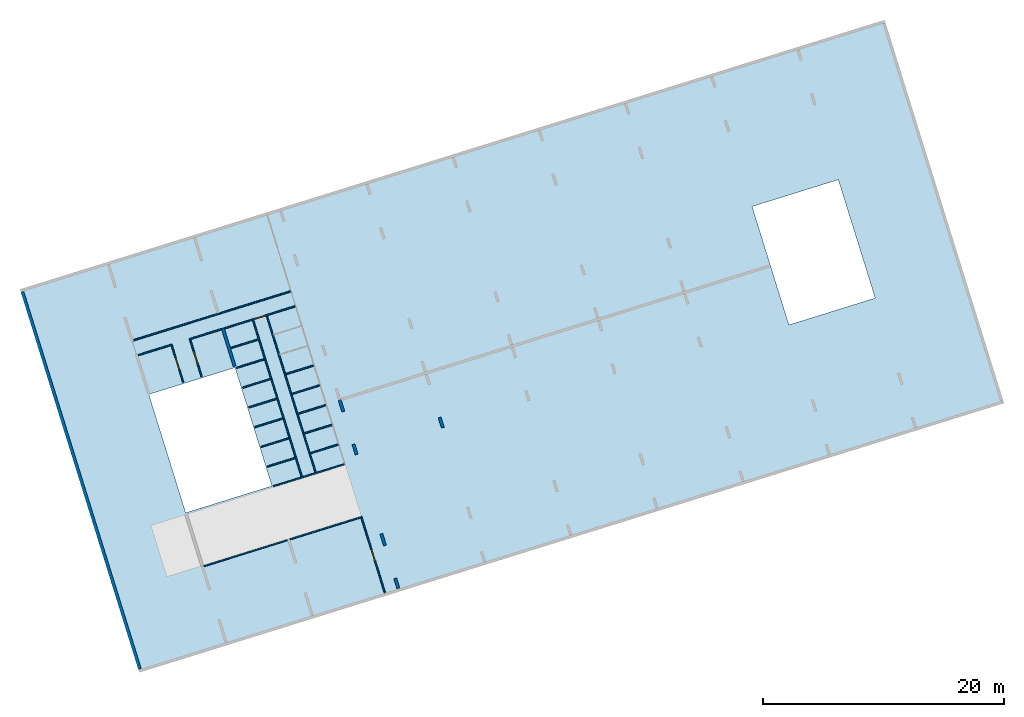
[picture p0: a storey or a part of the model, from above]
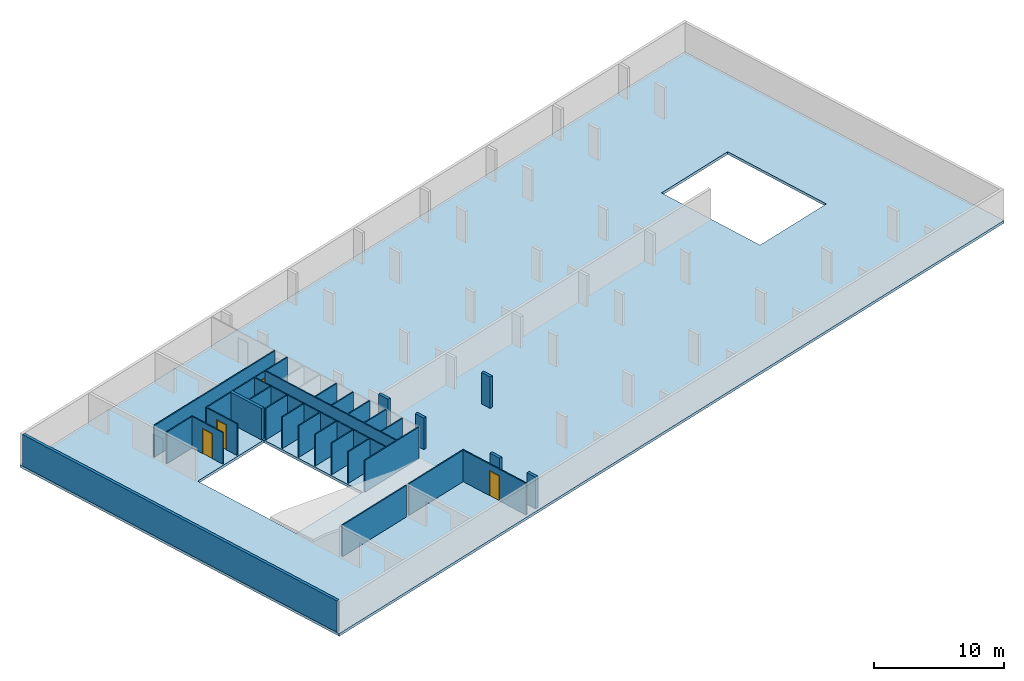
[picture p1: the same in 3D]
Properties of the parts of a building model (IFC4)

# File
Description: ViewDefinition [ReferenceView_V1.2], RevitIdentifiers [ContentGUID: 7b0fba1c-e461-43e6-a004-74300536da52, VersionGUID: d83a99a4-e321-4da3-b3c9-0b0068a0408a, NumberOfSaves: 137], Options [Excluded Entities: IfcGroup;], CoordinateReference [CoordinateBase: Survey Point, ProjectSite: Internal]
File name: MiniBIM 3.1 SO_00_VORM.ifc
Time: 2025-10-09T12:54:53+02:00
Organization: VORM Holding B.V.
Written by: IfcOpenShell 0.8.2
Made in: Bonsai 0.8.2

# IfcProject, 0000
LongName: Voorbeelmodel MiniBIM 3.1 SO-fase; Phase: PROJECTFASE

# IfcSite, Schiehaven
RefLatitude: 51, 54, 13, 78253; RefLongitude: 4, 27, 15, 99642; RefElevation: 3.5 m
Pset_SiteCommon - Reference: Project Information

# IfcBuilding, VORM huis
LongName: VORM huis
Pset_BuildingCommon - Reference: Project Information; NumberOfStoreys: 2; IsLandmarked: no
Pset_BuildingElementProxyCommon - Reference: Project Information; IsExternal: no
Pset_BuildingStoreyCommon - Reference: Project Information; AboveGround: no
Pset_BuildingSystemCommon - Reference: Project Information

# IfcBuildingStorey: Level:Level bouwniveau (PBP) (11)
In: VORM huis
Pset_BuildingStoreyCommon - Reference: Level bouwniveau (PBP)
Name | LongName | Elevation (m) | EntranceLevel | AboveGround
-1 kelder | -1 kelder | -3.2 | no | no
00 begane grond | begane grond | 0 | yes | yes
01 eerste verdieping | 01 eerste verdieping | 3.9 | no | yes
02 tweede verdieping | 02 tweede verdieping | 6.9 | no | yes
03 derde verdieping | 03 derde verdieping | 9.9 | no | yes
04 vierde verdieping | 04 vierde verdieping | 12.9 | no | yes
05 vijfde verdieping | 05 vijfde verdieping | 15.9 | no | yes
06 zesde verdieping | 06 zesde verdieping | 18.9 | no | yes
07 zevende verdieping | 07 zevende verdieping | 21.9 | no | yes
08 achtste verdieping | 08 achtste verdieping | 24.9 | no | yes
09 negende verdieping | 09 negende verdieping | 27.9 | no | yes

# IfcBuildingElementProxy: VORM_coordinatiepunt:CRS-coordinatiepunt, CRS-coordinatiepunt
In: 00 begane grond
Type - Classification: 00.00 (NL-SfB); Material: Blauw, Wit
Pset_BuildingElementProxyCommon - IsExternal: no; Reference: CRS-coordinatiepunt
Pset_EnvironmentalImpactIndicators - Reference: CRS-coordinatiepunt
Qto_BuildingElementProxyQuantities - NetSurfaceArea: 6.92096 m2; NetVolume: 0.458368 m3

# IfcBuildingElementProxy: VORM_coordinatiepunt:Lokaal-coordinatiepunt, Lokaal-coordinatiepunt
In: 00 begane grond
Type - Classification: 00.00 (NL-SfB); Material: Blauw, Wit
Pset_BuildingElementProxyCommon - Reference: Lokaal-coordinatiepunt; IsExternal: no
Pset_EnvironmentalImpactIndicators - Reference: Lokaal-coordinatiepunt
Qto_BuildingElementProxyQuantities - NetSurfaceArea: 7.78088 m2; NetVolume: 1.00022 m3

# IfcDoor: 32_DO_binnendeur enkel:binnendeur zelfsluitend 30min (7)
In: -1 kelder
Type - PredefinedType: DOOR; Classification: 32.30 binnenwandopeningen; gevuld met deuren, algemeen (verzamelniveau) (NL-SfB); Material: PD_a_binnenwandopeningen, metaal_aluminium_ntb
Type - Pset_DoorCommon - IsExternal: no; FireRating: 30
OverallHeight: 2.35 m; OverallWidth: 1.05 m
Pset_DoorCommon - Reference: binnendeur zelfsluitend 30min
Pset_EnvironmentalImpactIndicators - Reference: binnendeur zelfsluitend 30min
Qto_DoorBaseQuantities - Width: 1.05 m; Height: 2.35 m; Perimeter: 2 m; Area: 2.4675 m2
Name
3 x Vluchtdeur | MiniBIM ILS - BouwwerkNummer: 01
4 x Vluchtdeur

# IfcOpeningElement (14)
In: -1 kelder
PredefinedType: OPENING
Name | Depth (m) | Height (m) | Width (m)
4 x Constructieve wand | 0.25 | 2.4 | 2.55 | Pset_EnvironmentalImpactIndicators - Reference: 28_WA_skelet_wand 250mm_gen; sets with these values: 2
2 x Funderingvloer |  | 7.5 | 10.3 | Pset_EnvironmentalImpactIndicators - Reference: 13_FL_funderingvloer 250mm; sets with these values: 2
5 x Vluchtdeur | 0.1 | 1.05 | 2.35
Vluchtdeur | 0.1 | 2.35 | 1.05
Vluchtdeur | 0.25 | 1.05 | 2.35
Vluchtdeur | 3.048 | 2.35 | 1.05

# IfcRamp: 24_GM_TLB_hellingbaan:Stalling, Hellingbaan
In: -1 kelder
Classification: 24.20 trappen en hellingen; hellingen, algemeen (verzamelniveau) (NL-SfB); Material: beton_gewapend_ihw
Pset_EnvironmentalImpactIndicators - Reference: Stalling
Pset_RampCommon - IsExternal: no; Reference: Stalling
Pset_RampFlightCommon - Reference: Stalling; Slope: 12.1338 deg

# IfcSlab: Floor:13_FL_funderingvloer 250mm, Funderingvloer
In: -1 kelder
Type - PredefinedType: FLOOR; Material: beton_gewapend_ihw
Type - Pset_ReinforcementBarPitchOfSlab - Description: Funderingvloer
Type - Pset_SlabCommon - LoadBearing: yes
Classification: 13.20 vloeren op grondslag; constructief, algemeen (verzamelniveau) (NL-SfB)
Pset_EnvironmentalImpactIndicators - Reference: 13_FL_funderingvloer 250mm; sets with these values: 2
Pset_SlabCommon - IsExternal: no; LoadBearing: no; Reference: 13_FL_funderingvloer 250mm; PitchAngle: 0 deg
Qto_SlabBaseQuantities - Width: 33.35 m; Length: 75.25 m; Depth: 0.25 m; Perimeter: 946.194 m; GrossArea: 2509.59 m2; NetArea: 2355.09 m2; GrossVolume: 627.397 m3; NetVolume: 588.772 m3

# IfcSlab: Floor:28_FL_skelet_dakterrasvloer 250mm, Begaanbare dakvloer
In: 00 begane grond
Type - PredefinedType: ROOF; Material: beton_gewapend_ihw
Type - Pset_ReinforcementBarPitchOfSlab - Description: Begaanbare dakvloer
Type - Pset_SlabCommon - LoadBearing: yes
Classification: 27.10 daken; niet constructief, algemeen (verzamelniveau) (NL-SfB)
Pset_EnvironmentalImpactIndicators - Reference: 28_FL_skelet_dakterrasvloer 250mm; sets with these values: 2
Pset_SlabCommon - IsExternal: no; LoadBearing: no; PitchAngle: 0 deg; Reference: 28_FL_skelet_dakterrasvloer 250mm
Qto_SlabBaseQuantities - Width: 29.75 m; Length: 33.35 m; Depth: 0.25 m; Perimeter: 414.042 m; GrossArea: 992.163 m2; NetArea: 992.163 m2; GrossVolume: 248.041 m3; NetVolume: 248.041 m3

# IfcWall: Basic Wall:22_WA_afbouw_binnenwand 100mm_gen (27)
In: -1 kelder
Type - PredefinedType: STANDARD
Type - Pset_ReinforcementBarPitchOfWall - Description: Binnenwand
Type - Pset_WallCommon - LoadBearing: no
Classification: 22.10 binnenwanden; niet constructief, algemeen (verzamelniveau) (NL-SfB); Material: ntb_ntb_ntb
Qto_WallBaseQuantities - Height: 2.95 m; Width: 0.1 m
Pset_EnvironmentalImpactIndicators - Reference: 22_WA_afbouw_binnenwand 100mm_gen; sets with these values: 2
Pset_WallCommon - IsExternal: no; ExtendToStructure: no; Reference: 22_WA_afbouw_binnenwand 100mm_gen
Name | Length (m) | GrossFootprintArea (m2) | GrossVolume (m3) = NetVolume (m3) | GrossSideArea (m2) = NetSideArea (m2)
Binnenwand | 21.7 | 2.17 | 5.908 | 59.08
Binnenwand | 6.15 | 0.615 | 1.81425 | 18.1425
Binnenwand | 6.25 | 0.625 | 1.84375 | 18.4375
Binnenwand | 6.55 | 0.655 | 1.6855 | 16.855
Binnenwand | 7.25 | 0.725 | 2.13875 | 21.3875
3 x Binnenwand | 13.65 | 1.365 | 4.02675 | 40.2675
Binnenwand | 6.15 | 0.615 | 1.5675 | 15.675
Binnenwand | 3.2 | 0.32 | 0.69725 | 6.9725
Binnenwand | 3.3 | 0.33 | 0.72675 | 7.2675
Binnenwand | 2.85 | 0.285 | 0.84075 | 8.4075
Binnenwand | 2.8 | 0.28 | 0.826 | 8.26
14 x Binnenwand | 2.425 | 0.2425 | 0.715375 | 7.15375

# IfcWall: Basic Wall:28_WA_skelet_keerwand 250mm_gen (4)
In: -1 kelder
Type - PredefinedType: STANDARD
Type - Pset_ReinforcementBarPitchOfWall - Description: Constructieve keerwand
Type - Pset_WallCommon - LoadBearing: yes
Classification: 28.20 hoofddraagconstructies; wanden en vloeren, algemeen (verzamelniveau) (NL-SfB); Material: beton_gewapend_ihw
Qto_WallBaseQuantities - Height: 2.95 m; Width: 0.25 m
Pset_EnvironmentalImpactIndicators - Reference: 28_WA_skelet_keerwand 250mm_gen; sets with these values: 2
Pset_WallCommon - IsExternal: no; Reference: 28_WA_skelet_keerwand 250mm_gen; LoadBearing: no; ExtendToStructure: no
Name | Length (m) | GrossFootprintArea (m2) | GrossVolume (m3) = NetVolume (m3) | GrossSideArea (m2) = NetSideArea (m2)
2 x Constructieve keerwand | 32.85 | 8.2125 | 24.2269 | 96.9075
2 x Constructieve keerwand | 75.25 | 18.8125 | 55.4969 | 221.988

# IfcWall: Basic Wall:28_WA_skelet_wand 250mm_gen (55)
In: -1 kelder
Type - PredefinedType: STANDARD
Type - Pset_ReinforcementBarPitchOfWall - Description: Constructieve wand
Type - Pset_WallCommon - LoadBearing: yes
Classification: 28.20 hoofddraagconstructies; wanden en vloeren, algemeen (verzamelniveau) (NL-SfB); Material: beton_gewapend_ihw
Qto_WallBaseQuantities - Width: 0.25 m
Pset_EnvironmentalImpactIndicators - Reference: 28_WA_skelet_wand 250mm_gen; sets with these values: 2
Pset_WallCommon - IsExternal: no; LoadBearing: no; Reference: 28_WA_skelet_wand 250mm_gen
Name | Height (m) | Length (m) | GrossFootprintArea (m2) | GrossVolume (m3) | GrossSideArea (m2) = NetSideArea (m2) | NetVolume (m3) | ExtendToStructure
Constructieve wand | 2.95 | 37.25 | 9.3125 | 27.4719 | 109.888 | 27.4719 | no
Constructieve wand | 2.95 | 6.65 | 1.6625 | 3.37438 | 13.4975 | 3.37438 | no
Constructieve wand | 2.95 | 3.3 | 0.825 | 2.43375 | 9.735 | 2.43375 | no
32 x Constructieve wand | 2.95 | 0.9 | 0.225 | 0.66375 | 2.655 | 0.66375 | no
4 x Constructieve wand | 2.95 | 1.025 | 0.25625 | 0.755937 | 3.02375 | 0.755937 | no
10 x Constructieve wand | 2.95 | 1.025 | 0.25625 | 0.755937 | 3.02375 | 0.755938 | no
2 x Constructieve wand | 2.95 | 1.025 | 0.25625 | 0.755938 | 3.02375 | 0.755938 | no
Constructieve wand | 2.95 | 6.65 | 1.6625 | 3.37437 | 13.4975 | 3.37437 | no
Constructieve wand | 2.95 | 6.55 | 1.6375 | 3.30063 | 13.2025 | 3.30062 | no
Constructieve wand | 2.50596 | 4.5 | 1.125 | 2.81921 | 11.2768 | 2.78898 | yes
Constructieve wand | 2.95 | 11.15 | 2.7875 | 6.07625 | 24.305 | 6.07625 | no
